VERSION 5.4 ;
NAMESCASESENSITIVE ON ;
BUSBITCHARS "[]" ;
DIVIDERCHAR "/" ;
UNITS
  DATABASE MICRONS 2000 ;
END UNITS
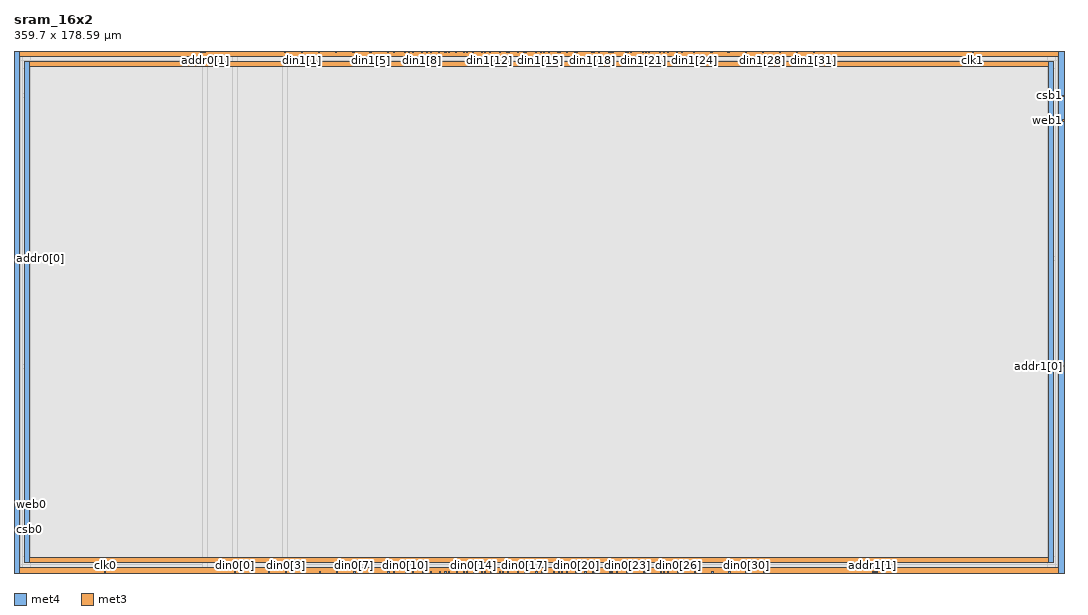
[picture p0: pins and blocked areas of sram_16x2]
MACRO sram_16x2
   CLASS BLOCK ;
   SIZE 359.7 BY 178.59 ;
   SYMMETRY X Y R90 ;
   PIN din0[0]
      DIRECTION INPUT ;
      PORT
         LAYER met4 ;
         RECT  75.56 0.0 75.94 0.38 ;
      END
   END din0[0]
   PIN din0[1]
      DIRECTION INPUT ;
      PORT
         LAYER met4 ;
         RECT  81.4 0.0 81.78 0.38 ;
      END
   END din0[1]
   PIN din0[2]
      DIRECTION INPUT ;
      PORT
         LAYER met4 ;
         RECT  87.24 0.0 87.62 0.38 ;
      END
   END din0[2]
   PIN din0[3]
      DIRECTION INPUT ;
      PORT
         LAYER met4 ;
         RECT  93.08 0.0 93.46 0.38 ;
      END
   END din0[3]
   PIN din0[4]
      DIRECTION INPUT ;
      PORT
         LAYER met4 ;
         RECT  98.92 0.0 99.3 0.38 ;
      END
   END din0[4]
   PIN din0[5]
      DIRECTION INPUT ;
      PORT
         LAYER met4 ;
         RECT  104.76 0.0 105.14 0.38 ;
      END
   END din0[5]
   PIN din0[6]
      DIRECTION INPUT ;
      PORT
         LAYER met4 ;
         RECT  110.6 0.0 110.98 0.38 ;
      END
   END din0[6]
   PIN din0[7]
      DIRECTION INPUT ;
      PORT
         LAYER met4 ;
         RECT  116.44 0.0 116.82 0.38 ;
      END
   END din0[7]
   PIN din0[8]
      DIRECTION INPUT ;
      PORT
         LAYER met4 ;
         RECT  122.28 0.0 122.66 0.38 ;
      END
   END din0[8]
   PIN din0[9]
      DIRECTION INPUT ;
      PORT
         LAYER met4 ;
         RECT  128.12 0.0 128.5 0.38 ;
      END
   END din0[9]
   PIN din0[10]
      DIRECTION INPUT ;
      PORT
         LAYER met4 ;
         RECT  133.96 0.0 134.34 0.38 ;
      END
   END din0[10]
   PIN din0[11]
      DIRECTION INPUT ;
      PORT
         LAYER met4 ;
         RECT  139.8 0.0 140.18 0.38 ;
      END
   END din0[11]
   PIN din0[12]
      DIRECTION INPUT ;
      PORT
         LAYER met4 ;
         RECT  145.64 0.0 146.02 0.38 ;
      END
   END din0[12]
   PIN din0[13]
      DIRECTION INPUT ;
      PORT
         LAYER met4 ;
         RECT  151.48 0.0 151.86 0.38 ;
      END
   END din0[13]
   PIN din0[14]
      DIRECTION INPUT ;
      PORT
         LAYER met4 ;
         RECT  157.32 0.0 157.7 0.38 ;
      END
   END din0[14]
   PIN din0[15]
      DIRECTION INPUT ;
      PORT
         LAYER met4 ;
         RECT  163.16 0.0 163.54 0.38 ;
      END
   END din0[15]
   PIN din0[16]
      DIRECTION INPUT ;
      PORT
         LAYER met4 ;
         RECT  169.0 0.0 169.38 0.38 ;
      END
   END din0[16]
   PIN din0[17]
      DIRECTION INPUT ;
      PORT
         LAYER met4 ;
         RECT  174.84 0.0 175.22 0.38 ;
      END
   END din0[17]
   PIN din0[18]
      DIRECTION INPUT ;
      PORT
         LAYER met4 ;
         RECT  180.68 0.0 181.06 0.38 ;
      END
   END din0[18]
   PIN din0[19]
      DIRECTION INPUT ;
      PORT
         LAYER met4 ;
         RECT  186.52 0.0 186.9 0.38 ;
      END
   END din0[19]
   PIN din0[20]
      DIRECTION INPUT ;
      PORT
         LAYER met4 ;
         RECT  192.36 0.0 192.74 0.38 ;
      END
   END din0[20]
   PIN din0[21]
      DIRECTION INPUT ;
      PORT
         LAYER met4 ;
         RECT  198.2 0.0 198.58 0.38 ;
      END
   END din0[21]
   PIN din0[22]
      DIRECTION INPUT ;
      PORT
         LAYER met4 ;
         RECT  204.04 0.0 204.42 0.38 ;
      END
   END din0[22]
   PIN din0[23]
      DIRECTION INPUT ;
      PORT
         LAYER met4 ;
         RECT  209.88 0.0 210.26 0.38 ;
      END
   END din0[23]
   PIN din0[24]
      DIRECTION INPUT ;
      PORT
         LAYER met4 ;
         RECT  215.72 0.0 216.1 0.38 ;
      END
   END din0[24]
   PIN din0[25]
      DIRECTION INPUT ;
      PORT
         LAYER met4 ;
         RECT  221.56 0.0 221.94 0.38 ;
      END
   END din0[25]
   PIN din0[26]
      DIRECTION INPUT ;
      PORT
         LAYER met4 ;
         RECT  227.4 0.0 227.78 0.38 ;
      END
   END din0[26]
   PIN din0[27]
      DIRECTION INPUT ;
      PORT
         LAYER met4 ;
         RECT  233.24 0.0 233.62 0.38 ;
      END
   END din0[27]
   PIN din0[28]
      DIRECTION INPUT ;
      PORT
         LAYER met4 ;
         RECT  239.08 0.0 239.46 0.38 ;
      END
   END din0[28]
   PIN din0[29]
      DIRECTION INPUT ;
      PORT
         LAYER met4 ;
         RECT  244.92 0.0 245.3 0.38 ;
      END
   END din0[29]
   PIN din0[30]
      DIRECTION INPUT ;
      PORT
         LAYER met4 ;
         RECT  250.76 0.0 251.14 0.38 ;
      END
   END din0[30]
   PIN din0[31]
      DIRECTION INPUT ;
      PORT
         LAYER met4 ;
         RECT  256.6 0.0 256.98 0.38 ;
      END
   END din0[31]
   PIN din1[0]
      DIRECTION INPUT ;
      PORT
         LAYER met4 ;
         RECT  92.74 178.21 93.12 178.59 ;
      END
   END din1[0]
   PIN din1[1]
      DIRECTION INPUT ;
      PORT
         LAYER met4 ;
         RECT  98.58 178.21 98.96 178.59 ;
      END
   END din1[1]
   PIN din1[2]
      DIRECTION INPUT ;
      PORT
         LAYER met4 ;
         RECT  104.42 178.21 104.8 178.59 ;
      END
   END din1[2]
   PIN din1[3]
      DIRECTION INPUT ;
      PORT
         LAYER met4 ;
         RECT  110.26 178.21 110.64 178.59 ;
      END
   END din1[3]
   PIN din1[4]
      DIRECTION INPUT ;
      PORT
         LAYER met4 ;
         RECT  116.1 178.21 116.48 178.59 ;
      END
   END din1[4]
   PIN din1[5]
      DIRECTION INPUT ;
      PORT
         LAYER met4 ;
         RECT  121.94 178.21 122.32 178.59 ;
      END
   END din1[5]
   PIN din1[6]
      DIRECTION INPUT ;
      PORT
         LAYER met4 ;
         RECT  127.78 178.21 128.16 178.59 ;
      END
   END din1[6]
   PIN din1[7]
      DIRECTION INPUT ;
      PORT
         LAYER met4 ;
         RECT  133.62 178.21 134.0 178.59 ;
      END
   END din1[7]
   PIN din1[8]
      DIRECTION INPUT ;
      PORT
         LAYER met4 ;
         RECT  139.46 178.21 139.84 178.59 ;
      END
   END din1[8]
   PIN din1[9]
      DIRECTION INPUT ;
      PORT
         LAYER met4 ;
         RECT  145.3 178.21 145.68 178.59 ;
      END
   END din1[9]
   PIN din1[10]
      DIRECTION INPUT ;
      PORT
         LAYER met4 ;
         RECT  151.14 178.21 151.52 178.59 ;
      END
   END din1[10]
   PIN din1[11]
      DIRECTION INPUT ;
      PORT
         LAYER met4 ;
         RECT  156.98 178.21 157.36 178.59 ;
      END
   END din1[11]
   PIN din1[12]
      DIRECTION INPUT ;
      PORT
         LAYER met4 ;
         RECT  162.82 178.21 163.2 178.59 ;
      END
   END din1[12]
   PIN din1[13]
      DIRECTION INPUT ;
      PORT
         LAYER met4 ;
         RECT  168.66 178.21 169.04 178.59 ;
      END
   END din1[13]
   PIN din1[14]
      DIRECTION INPUT ;
      PORT
         LAYER met4 ;
         RECT  174.5 178.21 174.88 178.59 ;
      END
   END din1[14]
   PIN din1[15]
      DIRECTION INPUT ;
      PORT
         LAYER met4 ;
         RECT  180.34 178.21 180.72 178.59 ;
      END
   END din1[15]
   PIN din1[16]
      DIRECTION INPUT ;
      PORT
         LAYER met4 ;
         RECT  186.18 178.21 186.56 178.59 ;
      END
   END din1[16]
   PIN din1[17]
      DIRECTION INPUT ;
      PORT
         LAYER met4 ;
         RECT  192.02 178.21 192.4 178.59 ;
      END
   END din1[17]
   PIN din1[18]
      DIRECTION INPUT ;
      PORT
         LAYER met4 ;
         RECT  197.86 178.21 198.24 178.59 ;
      END
   END din1[18]
   PIN din1[19]
      DIRECTION INPUT ;
      PORT
         LAYER met4 ;
         RECT  203.7 178.21 204.08 178.59 ;
      END
   END din1[19]
   PIN din1[20]
      DIRECTION INPUT ;
      PORT
         LAYER met4 ;
         RECT  209.54 178.21 209.92 178.59 ;
      END
   END din1[20]
   PIN din1[21]
      DIRECTION INPUT ;
      PORT
         LAYER met4 ;
         RECT  215.38 178.21 215.76 178.59 ;
      END
   END din1[21]
   PIN din1[22]
      DIRECTION INPUT ;
      PORT
         LAYER met4 ;
         RECT  221.22 178.21 221.6 178.59 ;
      END
   END din1[22]
   PIN din1[23]
      DIRECTION INPUT ;
      PORT
         LAYER met4 ;
         RECT  227.06 178.21 227.44 178.59 ;
      END
   END din1[23]
   PIN din1[24]
      DIRECTION INPUT ;
      PORT
         LAYER met4 ;
         RECT  232.9 178.21 233.28 178.59 ;
      END
   END din1[24]
   PIN din1[25]
      DIRECTION INPUT ;
      PORT
         LAYER met4 ;
         RECT  238.74 178.21 239.12 178.59 ;
      END
   END din1[25]
   PIN din1[26]
      DIRECTION INPUT ;
      PORT
         LAYER met4 ;
         RECT  244.58 178.21 244.96 178.59 ;
      END
   END din1[26]
   PIN din1[27]
      DIRECTION INPUT ;
      PORT
         LAYER met4 ;
         RECT  250.42 178.21 250.8 178.59 ;
      END
   END din1[27]
   PIN din1[28]
      DIRECTION INPUT ;
      PORT
         LAYER met4 ;
         RECT  256.26 178.21 256.64 178.59 ;
      END
   END din1[28]
   PIN din1[29]
      DIRECTION INPUT ;
      PORT
         LAYER met4 ;
         RECT  262.1 178.21 262.48 178.59 ;
      END
   END din1[29]
   PIN din1[30]
      DIRECTION INPUT ;
      PORT
         LAYER met4 ;
         RECT  267.94 178.21 268.32 178.59 ;
      END
   END din1[30]
   PIN din1[31]
      DIRECTION INPUT ;
      PORT
         LAYER met4 ;
         RECT  273.78 178.21 274.16 178.59 ;
      END
   END din1[31]
   PIN addr0[0]
      DIRECTION INPUT ;
      PORT
         LAYER met3 ;
         RECT  0.0 107.58 0.38 107.96 ;
      END
   END addr0[0]
   PIN addr0[1]
      DIRECTION INPUT ;
      PORT
         LAYER met4 ;
         RECT  65.315 178.21 65.695 178.59 ;
      END
   END addr0[1]
   PIN addr0[2]
      DIRECTION INPUT ;
      PORT
         LAYER met4 ;
         RECT  64.625 178.21 65.005 178.59 ;
      END
   END addr0[2]
   PIN addr0[3]
      DIRECTION INPUT ;
      PORT
         LAYER met4 ;
         RECT  63.88 178.21 64.26 178.59 ;
      END
   END addr0[3]
   PIN addr1[0]
      DIRECTION INPUT ;
      PORT
         LAYER met3 ;
         RECT  359.32 70.61 359.7 70.99 ;
      END
   END addr1[0]
   PIN addr1[1]
      DIRECTION INPUT ;
      PORT
         LAYER met4 ;
         RECT  294.005 0.0 294.385 0.38 ;
      END
   END addr1[1]
   PIN addr1[2]
      DIRECTION INPUT ;
      PORT
         LAYER met4 ;
         RECT  294.695 0.0 295.075 0.38 ;
      END
   END addr1[2]
   PIN addr1[3]
      DIRECTION INPUT ;
      PORT
         LAYER met4 ;
         RECT  295.44 0.0 295.82 0.38 ;
      END
   END addr1[3]
   PIN csb0
      DIRECTION INPUT ;
      PORT
         LAYER met3 ;
         RECT  0.0 14.87 0.38 15.25 ;
      END
   END csb0
   PIN csb1
      DIRECTION INPUT ;
      PORT
         LAYER met3 ;
         RECT  359.32 163.34 359.7 163.72 ;
      END
   END csb1
   PIN web0
      DIRECTION INPUT ;
      PORT
         LAYER met3 ;
         RECT  0.0 23.37 0.38 23.75 ;
      END
   END web0
   PIN web1
      DIRECTION INPUT ;
      PORT
         LAYER met3 ;
         RECT  359.32 154.84 359.7 155.22 ;
      END
   END web1
   PIN clk0
      DIRECTION INPUT ;
      PORT
         LAYER met4 ;
         RECT  31.1 0.0 31.48 0.38 ;
      END
   END clk0
   PIN clk1
      DIRECTION INPUT ;
      PORT
         LAYER met4 ;
         RECT  328.22 178.21 328.6 178.59 ;
      END
   END clk1
   PIN dout0[0]
      DIRECTION OUTPUT ;
      PORT
         LAYER met4 ;
         RECT  130.105 0.0 130.485 0.38 ;
      END
   END dout0[0]
   PIN dout0[1]
      DIRECTION OUTPUT ;
      PORT
         LAYER met4 ;
         RECT  135.135 0.0 135.515 0.38 ;
      END
   END dout0[1]
   PIN dout0[2]
      DIRECTION OUTPUT ;
      PORT
         LAYER met4 ;
         RECT  136.345 0.0 136.725 0.38 ;
      END
   END dout0[2]
   PIN dout0[3]
      DIRECTION OUTPUT ;
      PORT
         LAYER met4 ;
         RECT  141.375 0.0 141.755 0.38 ;
      END
   END dout0[3]
   PIN dout0[4]
      DIRECTION OUTPUT ;
      PORT
         LAYER met4 ;
         RECT  142.585 0.0 142.965 0.38 ;
      END
   END dout0[4]
   PIN dout0[5]
      DIRECTION OUTPUT ;
      PORT
         LAYER met4 ;
         RECT  147.615 0.0 147.995 0.38 ;
      END
   END dout0[5]
   PIN dout0[6]
      DIRECTION OUTPUT ;
      PORT
         LAYER met4 ;
         RECT  148.825 0.0 149.205 0.38 ;
      END
   END dout0[6]
   PIN dout0[7]
      DIRECTION OUTPUT ;
      PORT
         LAYER met4 ;
         RECT  153.855 0.0 154.235 0.38 ;
      END
   END dout0[7]
   PIN dout0[8]
      DIRECTION OUTPUT ;
      PORT
         LAYER met4 ;
         RECT  155.065 0.0 155.445 0.38 ;
      END
   END dout0[8]
   PIN dout0[9]
      DIRECTION OUTPUT ;
      PORT
         LAYER met4 ;
         RECT  160.095 0.0 160.475 0.38 ;
      END
   END dout0[9]
   PIN dout0[10]
      DIRECTION OUTPUT ;
      PORT
         LAYER met4 ;
         RECT  161.305 0.0 161.685 0.38 ;
      END
   END dout0[10]
   PIN dout0[11]
      DIRECTION OUTPUT ;
      PORT
         LAYER met4 ;
         RECT  166.335 0.0 166.715 0.38 ;
      END
   END dout0[11]
   PIN dout0[12]
      DIRECTION OUTPUT ;
      PORT
         LAYER met4 ;
         RECT  167.195 0.0 167.575 0.38 ;
      END
   END dout0[12]
   PIN dout0[13]
      DIRECTION OUTPUT ;
      PORT
         LAYER met4 ;
         RECT  172.575 0.0 172.955 0.38 ;
      END
   END dout0[13]
   PIN dout0[14]
      DIRECTION OUTPUT ;
      PORT
         LAYER met4 ;
         RECT  175.53 0.0 175.91 0.38 ;
      END
   END dout0[14]
   PIN dout0[15]
      DIRECTION OUTPUT ;
      PORT
         LAYER met4 ;
         RECT  178.815 0.0 179.195 0.38 ;
      END
   END dout0[15]
   PIN dout0[16]
      DIRECTION OUTPUT ;
      PORT
         LAYER met4 ;
         RECT  181.405 0.0 181.785 0.38 ;
      END
   END dout0[16]
   PIN dout0[17]
      DIRECTION OUTPUT ;
      PORT
         LAYER met4 ;
         RECT  184.715 0.0 185.095 0.38 ;
      END
   END dout0[17]
   PIN dout0[18]
      DIRECTION OUTPUT ;
      PORT
         LAYER met4 ;
         RECT  187.645 0.0 188.025 0.38 ;
      END
   END dout0[18]
   PIN dout0[19]
      DIRECTION OUTPUT ;
      PORT
         LAYER met4 ;
         RECT  189.355 0.0 189.735 0.38 ;
      END
   END dout0[19]
   PIN dout0[20]
      DIRECTION OUTPUT ;
      PORT
         LAYER met4 ;
         RECT  193.05 0.0 193.43 0.38 ;
      END
   END dout0[20]
   PIN dout0[21]
      DIRECTION OUTPUT ;
      PORT
         LAYER met4 ;
         RECT  195.595 0.0 195.975 0.38 ;
      END
   END dout0[21]
   PIN dout0[22]
      DIRECTION OUTPUT ;
      PORT
         LAYER met4 ;
         RECT  198.89 0.0 199.27 0.38 ;
      END
   END dout0[22]
   PIN dout0[23]
      DIRECTION OUTPUT ;
      PORT
         LAYER met4 ;
         RECT  204.73 0.0 205.11 0.38 ;
      END
   END dout0[23]
   PIN dout0[24]
      DIRECTION OUTPUT ;
      PORT
         LAYER met4 ;
         RECT  206.365 0.0 206.745 0.38 ;
      END
   END dout0[24]
   PIN dout0[25]
      DIRECTION OUTPUT ;
      PORT
         LAYER met4 ;
         RECT  210.57 0.0 210.95 0.38 ;
      END
   END dout0[25]
   PIN dout0[26]
      DIRECTION OUTPUT ;
      PORT
         LAYER met4 ;
         RECT  211.285 0.0 211.665 0.38 ;
      END
   END dout0[26]
   PIN dout0[27]
      DIRECTION OUTPUT ;
      PORT
         LAYER met4 ;
         RECT  216.41 0.0 216.79 0.38 ;
      END
   END dout0[27]
   PIN dout0[28]
      DIRECTION OUTPUT ;
      PORT
         LAYER met4 ;
         RECT  217.465 0.0 217.845 0.38 ;
      END
   END dout0[28]
   PIN dout0[29]
      DIRECTION OUTPUT ;
      PORT
         LAYER met4 ;
         RECT  222.495 0.0 222.875 0.38 ;
      END
   END dout0[29]
   PIN dout0[30]
      DIRECTION OUTPUT ;
      PORT
         LAYER met4 ;
         RECT  223.705 0.0 224.085 0.38 ;
      END
   END dout0[30]
   PIN dout0[31]
      DIRECTION OUTPUT ;
      PORT
         LAYER met4 ;
         RECT  228.735 0.0 229.115 0.38 ;
      END
   END dout0[31]
   PIN dout1[0]
      DIRECTION OUTPUT ;
      PORT
         LAYER met4 ;
         RECT  130.105 178.21 130.485 178.59 ;
      END
   END dout1[0]
   PIN dout1[1]
      DIRECTION OUTPUT ;
      PORT
         LAYER met4 ;
         RECT  135.135 178.21 135.515 178.59 ;
      END
   END dout1[1]
   PIN dout1[2]
      DIRECTION OUTPUT ;
      PORT
         LAYER met4 ;
         RECT  136.345 178.21 136.725 178.59 ;
      END
   END dout1[2]
   PIN dout1[3]
      DIRECTION OUTPUT ;
      PORT
         LAYER met4 ;
         RECT  141.375 178.21 141.755 178.59 ;
      END
   END dout1[3]
   PIN dout1[4]
      DIRECTION OUTPUT ;
      PORT
         LAYER met4 ;
         RECT  142.585 178.21 142.965 178.59 ;
      END
   END dout1[4]
   PIN dout1[5]
      DIRECTION OUTPUT ;
      PORT
         LAYER met4 ;
         RECT  147.615 178.21 147.995 178.59 ;
      END
   END dout1[5]
   PIN dout1[6]
      DIRECTION OUTPUT ;
      PORT
         LAYER met4 ;
         RECT  148.825 178.21 149.205 178.59 ;
      END
   END dout1[6]
   PIN dout1[7]
      DIRECTION OUTPUT ;
      PORT
         LAYER met4 ;
         RECT  153.855 178.21 154.235 178.59 ;
      END
   END dout1[7]
   PIN dout1[8]
      DIRECTION OUTPUT ;
      PORT
         LAYER met4 ;
         RECT  155.065 178.21 155.445 178.59 ;
      END
   END dout1[8]
   PIN dout1[9]
      DIRECTION OUTPUT ;
      PORT
         LAYER met4 ;
         RECT  160.095 178.21 160.475 178.59 ;
      END
   END dout1[9]
   PIN dout1[10]
      DIRECTION OUTPUT ;
      PORT
         LAYER met4 ;
         RECT  161.015 178.21 161.395 178.59 ;
      END
   END dout1[10]
   PIN dout1[11]
      DIRECTION OUTPUT ;
      PORT
         LAYER met4 ;
         RECT  166.335 178.21 166.715 178.59 ;
      END
   END dout1[11]
   PIN dout1[12]
      DIRECTION OUTPUT ;
      PORT
         LAYER met4 ;
         RECT  169.35 178.21 169.73 178.59 ;
      END
   END dout1[12]
   PIN dout1[13]
      DIRECTION OUTPUT ;
      PORT
         LAYER met4 ;
         RECT  172.575 178.21 172.955 178.59 ;
      END
   END dout1[13]
   PIN dout1[14]
      DIRECTION OUTPUT ;
      PORT
         LAYER met4 ;
         RECT  175.19 178.21 175.57 178.59 ;
      END
   END dout1[14]
   PIN dout1[15]
      DIRECTION OUTPUT ;
      PORT
         LAYER met4 ;
         RECT  178.535 178.21 178.915 178.59 ;
      END
   END dout1[15]
   PIN dout1[16]
      DIRECTION OUTPUT ;
      PORT
         LAYER met4 ;
         RECT  181.405 178.21 181.785 178.59 ;
      END
   END dout1[16]
   PIN dout1[17]
      DIRECTION OUTPUT ;
      PORT
         LAYER met4 ;
         RECT  183.115 178.21 183.495 178.59 ;
      END
   END dout1[17]
   PIN dout1[18]
      DIRECTION OUTPUT ;
      PORT
         LAYER met4 ;
         RECT  186.87 178.21 187.25 178.59 ;
      END
   END dout1[18]
   PIN dout1[19]
      DIRECTION OUTPUT ;
      PORT
         LAYER met4 ;
         RECT  189.355 178.21 189.735 178.59 ;
      END
   END dout1[19]
   PIN dout1[20]
      DIRECTION OUTPUT ;
      PORT
         LAYER met4 ;
         RECT  192.71 178.21 193.09 178.59 ;
      END
   END dout1[20]
   PIN dout1[21]
      DIRECTION OUTPUT ;
      PORT
         LAYER met4 ;
         RECT  198.55 178.21 198.93 178.59 ;
      END
   END dout1[21]
   PIN dout1[22]
      DIRECTION OUTPUT ;
      PORT
         LAYER met4 ;
         RECT  200.125 178.21 200.505 178.59 ;
      END
   END dout1[22]
   PIN dout1[23]
      DIRECTION OUTPUT ;
      PORT
         LAYER met4 ;
         RECT  204.39 178.21 204.77 178.59 ;
      END
   END dout1[23]
   PIN dout1[24]
      DIRECTION OUTPUT ;
      PORT
         LAYER met4 ;
         RECT  205.08 178.21 205.46 178.59 ;
      END
   END dout1[24]
   PIN dout1[25]
      DIRECTION OUTPUT ;
      PORT
         LAYER met4 ;
         RECT  210.23 178.21 210.61 178.59 ;
      END
   END dout1[25]
   PIN dout1[26]
      DIRECTION OUTPUT ;
      PORT
         LAYER met4 ;
         RECT  211.225 178.21 211.605 178.59 ;
      END
   END dout1[26]
   PIN dout1[27]
      DIRECTION OUTPUT ;
      PORT
         LAYER met4 ;
         RECT  216.255 178.21 216.635 178.59 ;
      END
   END dout1[27]
   PIN dout1[28]
      DIRECTION OUTPUT ;
      PORT
         LAYER met4 ;
         RECT  217.465 178.21 217.845 178.59 ;
      END
   END dout1[28]
   PIN dout1[29]
      DIRECTION OUTPUT ;
      PORT
         LAYER met4 ;
         RECT  222.495 178.21 222.875 178.59 ;
      END
   END dout1[29]
   PIN dout1[30]
      DIRECTION OUTPUT ;
      PORT
         LAYER met4 ;
         RECT  223.705 178.21 224.085 178.59 ;
      END
   END dout1[30]
   PIN dout1[31]
      DIRECTION OUTPUT ;
      PORT
         LAYER met4 ;
         RECT  228.735 178.21 229.115 178.59 ;
      END
   END dout1[31]
   PIN vccd1
      DIRECTION INOUT ;
      USE POWER ; 
      SHAPE ABUTMENT ; 
      PORT
         LAYER met4 ;
         RECT  357.96 0.0 359.7 178.59 ;
         LAYER met3 ;
         RECT  0.0 176.85 359.7 178.59 ;
         LAYER met3 ;
         RECT  0.0 0.0 359.7 1.74 ;
         LAYER met4 ;
         RECT  0.0 0.0 1.74 178.59 ;
      END
   END vccd1
   PIN vssd1
      DIRECTION INOUT ;
      USE GROUND ; 
      SHAPE ABUTMENT ; 
      PORT
         LAYER met3 ;
         RECT  3.48 3.48 356.22 5.22 ;
         LAYER met4 ;
         RECT  3.48 3.48 5.22 175.11 ;
         LAYER met3 ;
         RECT  3.48 173.37 356.22 175.11 ;
         LAYER met4 ;
         RECT  354.48 3.48 356.22 175.11 ;
      END
   END vssd1
   OBS
   LAYER  met1 ;
      RECT  0.62 0.62 359.08 177.97 ;
   LAYER  met2 ;
      RECT  0.62 0.62 359.08 177.97 ;
   LAYER  met3 ;
      RECT  0.98 106.98 359.08 108.56 ;
      RECT  0.98 70.01 358.72 71.59 ;
      RECT  0.98 71.59 358.72 106.98 ;
      RECT  358.72 71.59 359.08 106.98 ;
      RECT  0.98 108.56 358.72 162.74 ;
      RECT  0.98 162.74 358.72 164.32 ;
      RECT  0.62 15.85 0.98 22.77 ;
      RECT  0.62 24.35 0.98 106.98 ;
      RECT  358.72 108.56 359.08 154.24 ;
      RECT  358.72 155.82 359.08 162.74 ;
      RECT  0.62 108.56 0.98 176.25 ;
      RECT  358.72 164.32 359.08 176.25 ;
      RECT  358.72 2.34 359.08 70.01 ;
      RECT  0.62 2.34 0.98 14.27 ;
      RECT  0.98 2.34 2.88 2.88 ;
      RECT  0.98 2.88 2.88 5.82 ;
      RECT  0.98 5.82 2.88 70.01 ;
      RECT  2.88 2.34 356.82 2.88 ;
      RECT  2.88 5.82 356.82 70.01 ;
      RECT  356.82 2.34 358.72 2.88 ;
      RECT  356.82 2.88 358.72 5.82 ;
      RECT  356.82 5.82 358.72 70.01 ;
      RECT  0.98 164.32 2.88 172.77 ;
      RECT  0.98 172.77 2.88 175.71 ;
      RECT  0.98 175.71 2.88 176.25 ;
      RECT  2.88 164.32 356.82 172.77 ;
      RECT  2.88 175.71 356.82 176.25 ;
      RECT  356.82 164.32 358.72 172.77 ;
      RECT  356.82 172.77 358.72 175.71 ;
      RECT  356.82 175.71 358.72 176.25 ;
   LAYER  met4 ;
      RECT  74.96 0.98 76.54 177.97 ;
      RECT  76.54 0.62 80.8 0.98 ;
      RECT  82.38 0.62 86.64 0.98 ;
      RECT  88.22 0.62 92.48 0.98 ;
      RECT  94.06 0.62 98.32 0.98 ;
      RECT  99.9 0.62 104.16 0.98 ;
      RECT  105.74 0.62 110.0 0.98 ;
      RECT  111.58 0.62 115.84 0.98 ;
      RECT  117.42 0.62 121.68 0.98 ;
      RECT  123.26 0.62 127.52 0.98 ;
      RECT  234.22 0.62 238.48 0.98 ;
      RECT  240.06 0.62 244.32 0.98 ;
      RECT  245.9 0.62 250.16 0.98 ;
      RECT  251.74 0.62 256.0 0.98 ;
      RECT  76.54 0.98 92.14 177.61 ;
      RECT  76.54 177.61 92.14 177.97 ;
      RECT  92.14 0.98 93.72 177.61 ;
      RECT  93.72 177.61 97.98 177.97 ;
      RECT  99.56 177.61 103.82 177.97 ;
      RECT  105.4 177.61 109.66 177.97 ;
      RECT  111.24 177.61 115.5 177.97 ;
      RECT  117.08 177.61 121.34 177.97 ;
      RECT  122.92 177.61 127.18 177.97 ;
      RECT  233.88 177.61 238.14 177.97 ;
      RECT  239.72 177.61 243.98 177.97 ;
      RECT  245.56 177.61 249.82 177.97 ;
      RECT  251.4 177.61 255.66 177.97 ;
      RECT  257.24 177.61 261.5 177.97 ;
      RECT  263.08 177.61 267.34 177.97 ;
      RECT  268.92 177.61 273.18 177.97 ;
      RECT  64.715 0.98 66.295 177.61 ;
      RECT  66.295 0.98 74.96 177.61 ;
      RECT  66.295 177.61 74.96 177.97 ;
      RECT  257.58 0.62 293.405 0.98 ;
      RECT  32.08 0.62 74.96 0.98 ;
      RECT  274.76 177.61 327.62 177.97 ;
      RECT  129.1 0.62 129.505 0.98 ;
      RECT  131.085 0.62 133.36 0.98 ;
      RECT  137.325 0.62 139.2 0.98 ;
      RECT  143.565 0.62 145.04 0.98 ;
      RECT  146.62 0.62 147.015 0.98 ;
      RECT  149.805 0.62 150.88 0.98 ;
      RECT  152.46 0.62 153.255 0.98 ;
      RECT  156.045 0.62 156.72 0.98 ;
      RECT  158.3 0.62 159.495 0.98 ;
      RECT  162.285 0.62 162.56 0.98 ;
      RECT  164.14 0.62 165.735 0.98 ;
      RECT  168.175 0.62 168.4 0.98 ;
      RECT  169.98 0.62 171.975 0.98 ;
      RECT  173.555 0.62 174.24 0.98 ;
      RECT  176.51 0.62 178.215 0.98 ;
      RECT  179.795 0.62 180.08 0.98 ;
      RECT  182.385 0.62 184.115 0.98 ;
      RECT  185.695 0.62 185.92 0.98 ;
      RECT  188.625 0.62 188.755 0.98 ;
      RECT  190.335 0.62 191.76 0.98 ;
      RECT  194.03 0.62 194.995 0.98 ;
      RECT  196.575 0.62 197.6 0.98 ;
      RECT  199.87 0.62 203.44 0.98 ;
      RECT  205.71 0.62 205.765 0.98 ;
      RECT  207.345 0.62 209.28 0.98 ;
      RECT  212.265 0.62 215.12 0.98 ;
      RECT  218.445 0.62 220.96 0.98 ;
      RECT  224.685 0.62 226.8 0.98 ;
      RECT  229.715 0.62 232.64 0.98 ;
      RECT  128.76 177.61 129.505 177.97 ;
      RECT  131.085 177.61 133.02 177.97 ;
      RECT  137.325 177.61 138.86 177.97 ;
      RECT  140.44 177.61 140.775 177.97 ;
      RECT  143.565 177.61 144.7 177.97 ;
      RECT  146.28 177.61 147.015 177.97 ;
      RECT  149.805 177.61 150.54 177.97 ;
      RECT  152.12 177.61 153.255 177.97 ;
      RECT  156.045 177.61 156.38 177.97 ;
      RECT  157.96 177.61 159.495 177.97 ;
      RECT  161.995 177.61 162.22 177.97 ;
      RECT  163.8 177.61 165.735 177.97 ;
      RECT  167.315 177.61 168.06 177.97 ;
      RECT  170.33 177.61 171.975 177.97 ;
      RECT  173.555 177.61 173.9 177.97 ;
      RECT  176.17 177.61 177.935 177.97 ;
      RECT  179.515 177.61 179.74 177.97 ;
      RECT  182.385 177.61 182.515 177.97 ;
      RECT  184.095 177.61 185.58 177.97 ;
      RECT  187.85 177.61 188.755 177.97 ;
      RECT  190.335 177.61 191.42 177.97 ;
      RECT  193.69 177.61 197.26 177.97 ;
      RECT  201.105 177.61 203.1 177.97 ;
      RECT  206.06 177.61 208.94 177.97 ;
      RECT  212.205 177.61 214.78 177.97 ;
      RECT  218.445 177.61 220.62 177.97 ;
      RECT  224.685 177.61 226.46 177.97 ;
      RECT  228.04 177.61 228.135 177.97 ;
      RECT  229.715 177.61 232.3 177.97 ;
      RECT  296.42 0.62 357.36 0.98 ;
      RECT  329.2 177.61 357.36 177.97 ;
      RECT  2.34 177.61 63.28 177.97 ;
      RECT  2.34 0.62 30.5 0.98 ;
      RECT  2.34 0.98 2.88 2.88 ;
      RECT  2.34 2.88 2.88 175.71 ;
      RECT  2.34 175.71 2.88 177.61 ;
      RECT  2.88 0.98 5.82 2.88 ;
      RECT  2.88 175.71 5.82 177.61 ;
      RECT  5.82 0.98 64.715 2.88 ;
      RECT  5.82 2.88 64.715 175.71 ;
      RECT  5.82 175.71 64.715 177.61 ;
      RECT  93.72 0.98 353.88 2.88 ;
      RECT  93.72 2.88 353.88 175.71 ;
      RECT  93.72 175.71 353.88 177.61 ;
      RECT  353.88 0.98 356.82 2.88 ;
      RECT  353.88 175.71 356.82 177.61 ;
      RECT  356.82 0.98 357.36 2.88 ;
      RECT  356.82 2.88 357.36 175.71 ;
      RECT  356.82 175.71 357.36 177.61 ;
   END
END    sram_16x2
END    LIBRARY
